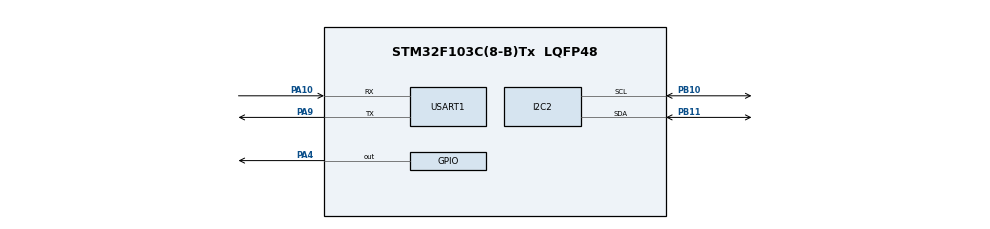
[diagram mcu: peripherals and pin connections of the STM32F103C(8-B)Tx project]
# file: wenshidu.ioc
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Mcu.Family=STM32F1
Mcu.Name=STM32F103C(8-B)Tx
Mcu.Package=LQFP48
NVIC.PriorityGroup=NVIC_PRIORITYGROUP_4
PA10.Mode=Asynchronous
PA10.Signal=USART1_RX
PA13.Mode=Serial_Wire
PA13.Signal=SYS_JTMS-SWDIO
PA14.Mode=Serial_Wire
PA14.Signal=SYS_JTCK-SWCLK
PA4.Signal=GPIO_Output
PA9.Mode=Asynchronous
PA9.Signal=USART1_TX
PB10.Mode=I2C
PB10.Signal=I2C2_SCL
PB11.Mode=I2C
PB11.Signal=I2C2_SDA
PC14-OSC32_IN.Mode=LSE-External-Oscillator
PC14-OSC32_IN.Signal=RCC_OSC32_IN
PC15-OSC32_OUT.Mode=LSE-External-Oscillator
PC15-OSC32_OUT.Signal=RCC_OSC32_OUT
PD0-OSC_IN.Mode=HSE-External-Oscillator
PD0-OSC_IN.Signal=RCC_OSC_IN
PD1-OSC_OUT.Mode=HSE-External-Oscillator
PD1-OSC_OUT.Signal=RCC_OSC_OUT
ProjectManager.HeapSize=0x200
ProjectManager.StackSize=0x400
ProjectManager.TargetToolchain=MDK-ARM V5
RCC.AHBFreq_Value=16000000
RCC.APB1Freq_Value=16000000
RCC.APB1TimFreq_Value=16000000
RCC.APB2Freq_Value=16000000
RCC.APB2TimFreq_Value=16000000
RCC.HCLKFreq_Value=16000000
RCC.PLLSourceVirtual=RCC_PLLSOURCE_HSE
RCC.SYSCLKFreq_VALUE=16000000
RCC.SYSCLKSource=RCC_SYSCLKSOURCE_PLLCLK
RCC.USBFreq_Value=16000000
USART1.VirtualMode=VM_ASYNC
board=custom

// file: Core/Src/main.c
/* USER CODE BEGIN Header */
/**
  ******************************************************************************
  * @file           : main.c
  * @brief          : Main program body
  ******************************************************************************
  * @attention
  *
  * Copyright (c) 2025 STMicroelectronics.
  * All rights reserved.
  *
  * This software is licensed under terms that can be found in the LICENSE file
  * in the root directory of this software component.
  * If no LICENSE file comes with this software, it is provided AS-IS.
  *
  ******************************************************************************
  */
/* USER CODE END Header */
#include "main.h"
#include "i2c.h"
#include "usart.h"
#include "gpio.h"

/* USER CODE BEGIN Includes */
#include <stdio.h>
#include <string.h>
/* USER CODE END Includes */

void SystemClock_Config(void);

/* USER CODE BEGIN 0 */
void AHT20_Init(){		//AHT20?????
	uint8_t read;
	uint8_t sendBE[3]={0xBE,0x08,0x00};	//?????
	HAL_Delay(40);							//?????40ms
	HAL_I2C_Master_Receive(&hi2c2,0x70,&read,1,HAL_MAX_DELAY);	//???????

	if((read & 0x08)==0x00){	//??????3????1
		HAL_I2C_Master_Transmit(&hi2c2,0x70,sendBE,3,HAL_MAX_DELAY);	//???????
		HAL_Delay(10);
	}
}

void AHT20_RE(float *T,float *RH){		//???????
	uint8_t sendAC[3]={0xAC,0x33,0x00};	//AC??????
	uint8_t readData[6];

	HAL_I2C_Master_Transmit(&hi2c2,0x70,sendAC,3,HAL_MAX_DELAY);	//??????
	HAL_Delay(80);
	HAL_I2C_Master_Receive(&hi2c2,0x70,readData,6,HAL_MAX_DELAY);	//??????

	if((readData[0] & 0x80)==0x00){	//???7????1
		uint32_t data=0;
		data =((uint32_t)readData[3]>>4)+((uint32_t)readData[2]<<4)+((uint32_t)readData[1]<<12);//??????
		*RH=data*100.0f/(1<<20);	//????

		data =(((uint32_t)readData[3] & 0x0F)<<16)+((uint32_t)readData[4]<<8)+((uint32_t)readData[5]);//??????
		*T=data*200.0f/(1<<20)-50;	//????
	}
}
/* USER CODE END 0 */

int main(void)
{

  /* MCU Configuration--------------------------------------------------------*/

  /* Reset of all peripherals, Initializes the Flash interface and the Systick. */
  HAL_Init();

  /* Configure the system clock */
  SystemClock_Config();

  /* Initialize all configured peripherals */
  MX_GPIO_Init();
  MX_I2C2_Init();
  MX_USART1_UART_Init();
  /* USER CODE BEGIN 2 */
  AHT20_Init();
  float T,RH;
  char message[50];
  /* USER CODE END 2 */

  /* Infinite loop */
  while (1)
  {

    /* USER CODE BEGIN 3 */
	  AHT20_RE(&T,&RH);	//?????????
	  sprintf(message,"??:%.1f?,??:%.1f %%\r\n",T,RH);	//??????
	  HAL_UART_Transmit(&huart1,(uint8_t*)message,strlen(message),HAL_MAX_DELAY);	//??????
	  HAL_Delay(2000);	//??2s
  }
  /* USER CODE END 3 */
}

void SystemClock_Config(void)
{
  RCC_OscInitTypeDef RCC_OscInitStruct = {0};
  RCC_ClkInitTypeDef RCC_ClkInitStruct = {0};

  /** Initializes the RCC Oscillators according to the specified parameters
  * in the RCC_OscInitTypeDef structure.
  */
  RCC_OscInitStruct.OscillatorType = RCC_OSCILLATORTYPE_HSI;
  RCC_OscInitStruct.HSIState = RCC_HSI_ON;
  RCC_OscInitStruct.HSICalibrationValue = RCC_HSICALIBRATION_DEFAULT;
  RCC_OscInitStruct.PLL.PLLState = RCC_PLL_NONE;
  if (HAL_RCC_OscConfig(&RCC_OscInitStruct) != HAL_OK)
  {
    Error_Handler();
  }

  /** Initializes the CPU, AHB and APB buses clocks
  */
  RCC_ClkInitStruct.ClockType = RCC_CLOCKTYPE_HCLK|RCC_CLOCKTYPE_SYSCLK
                              |RCC_CLOCKTYPE_PCLK1|RCC_CLOCKTYPE_PCLK2;
  RCC_ClkInitStruct.SYSCLKSource = RCC_SYSCLKSOURCE_HSI;
  RCC_ClkInitStruct.AHBCLKDivider = RCC_SYSCLK_DIV1;
  RCC_ClkInitStruct.APB1CLKDivider = RCC_HCLK_DIV1;
  RCC_ClkInitStruct.APB2CLKDivider = RCC_HCLK_DIV1;

  if (HAL_RCC_ClockConfig(&RCC_ClkInitStruct, FLASH_LATENCY_0) != HAL_OK)
  {
    Error_Handler();
  }
}

void Error_Handler(void)
{
  __disable_irq();
  while (1)
  {
  }
}
